VERSION 5.7 ;
BUSBITCHARS "[]" ;
DIVIDERCHAR "/" ;

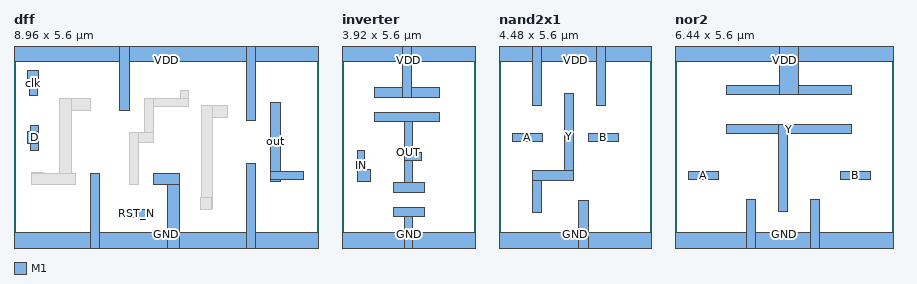
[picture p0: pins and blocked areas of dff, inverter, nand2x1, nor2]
MACRO dff
  CLASS CORE ;
  ORIGIN 0.28 0 ;
  FOREIGN dff -0.28 0 ;
  SIZE 8.96 BY 5.6 ;
  SYMMETRY X Y ;
  SITE core ;
  PIN D
    DIRECTION INOUT ;
    USE SIGNAL ;
    PORT
      LAYER M1 ;
        RECT 0.22 2.705 0.45 3.445 ;
        RECT 0.11 2.91 0.45 3.25 ;
    END
  END D
  PIN clk
    DIRECTION INPUT ;
    USE CLOCK ;
    PORT
      LAYER M1 ;
        RECT 0.115 4.705 0.455 5.045 ;
        RECT 0.17 4.32 0.4 5.045 ;
    END
  END clk
  PIN out
    DIRECTION INOUT ;
    USE SIGNAL ;
    PORT
      LAYER M1 ;
        RECT 7.28 1.845 8.24 2.075 ;
        RECT 7.28 1.795 7.56 4.105 ;
    END
  END out
  PIN RST_N
    DIRECTION INPUT ;
    USE SIGNAL ;
    PORT
      LAYER M1 ;
        RECT 2.87 0.725 3.78 0.955 ;
    END
  END RST_N
  PIN VDD
    DIRECTION INOUT ;
    USE POWER ;
    SHAPE ABUTMENT ;
    PORT
      LAYER M1 ;
        RECT -0.28 5.32 8.68 5.88 ;
        RECT 6.56 3.585 6.84 5.88 ;
        RECT 2.835 3.89 3.115 5.88 ;
    END
  END VDD
  PIN GND
    DIRECTION INOUT ;
    USE GROUND ;
    SHAPE ABUTMENT ;
    PORT
      LAYER M1 ;
        RECT -0.28 -0.28 8.68 0.28 ;
        RECT 6.56 -0.28 6.84 2.315 ;
        RECT 3.83 1.685 4.595 2.025 ;
        RECT 4.255 -0.28 4.595 2.025 ;
        RECT 1.96 -0.28 2.24 2.025 ;
    END
  END GND
  OBS
    LAYER M1 ;
      RECT 5.24 3.675 6.01 4.015 ;
      RECT 5.24 0.98 5.58 4.015 ;
      RECT 5.21 0.96 5.55 1.3 ;
      RECT 4.625 4 4.855 4.475 ;
      RECT 3.555 4 4.855 4.23 ;
      RECT 3.555 2.94 3.835 4.23 ;
      RECT 3.11 2.94 3.835 3.22 ;
      RECT 3.11 1.685 3.39 3.22 ;
      RECT 1.075 3.89 1.965 4.23 ;
      RECT 1.075 1.685 1.415 4.23 ;
      RECT 0.245 1.685 0.585 2.04 ;
      RECT 0.245 1.685 1.52 2.025 ;
  END
END dff

MACRO inverter
  CLASS CORE ;
  ORIGIN 0.28 0 ;
  FOREIGN inverter -0.28 0 ;
  SIZE 3.92 BY 5.6 ;
  SYMMETRY X Y ;
  SITE core ;
  PIN GND
    DIRECTION INOUT ;
    USE GROUND ;
    SHAPE ABUTMENT ;
    PORT
      LAYER M1 ;
        RECT -0.28 -0.28 3.64 0.28 ;
        RECT 1.23 0.74 2.15 1.02 ;
        RECT 1.56 -0.28 1.79 1.02 ;
    END
  END GND
  PIN OUT
    DIRECTION OUTPUT ;
    USE SIGNAL ;
    PORT
      LAYER M1 ;
        RECT 0.67 3.545 2.59 3.825 ;
        RECT 1.23 1.46 2.15 1.74 ;
        RECT 1.575 2.405 2.075 2.635 ;
        RECT 1.575 1.46 1.805 3.825 ;
    END
  END OUT
  PIN IN
    DIRECTION INPUT ;
    USE SIGNAL ;
    PORT
      LAYER M1 ;
        RECT 0.165 1.79 0.565 2.13 ;
        RECT 0.165 1.79 0.395 2.705 ;
    END
  END IN
  PIN VDD
    DIRECTION INOUT ;
    USE POWER ;
    SHAPE ABUTMENT ;
    PORT
      LAYER M1 ;
        RECT -0.28 5.32 3.64 5.88 ;
        RECT 0.67 4.265 2.59 4.545 ;
        RECT 1.49 4.265 1.77 5.88 ;
    END
  END VDD
END inverter

MACRO nand2x1
  CLASS CORE ;
  ORIGIN 0.28 0 ;
  FOREIGN nand2x1 -0.28 0 ;
  SIZE 4.48 BY 5.6 ;
  SYMMETRY X Y ;
  SITE core ;
  PIN VDD
    DIRECTION INOUT ;
    USE POWER ;
    SHAPE ABUTMENT ;
    PORT
      LAYER M1 ;
        RECT -0.28 5.32 4.2 5.88 ;
        RECT 2.58 4.03 2.86 5.88 ;
        RECT 0.7 4.03 0.98 5.88 ;
    END
  END VDD
  PIN A
    DIRECTION INPUT ;
    USE SIGNAL ;
    PORT
      LAYER M1 ;
        RECT 0.11 2.965 0.99 3.195 ;
    END
  END A
  PIN Y
    DIRECTION OUTPUT ;
    USE SIGNAL ;
    PORT
      LAYER M1 ;
        RECT 1.64 1.82 1.92 4.37 ;
        RECT 0.7 1.82 1.92 2.1 ;
        RECT 0.7 0.87 0.98 2.1 ;
    END
  END Y
  PIN B
    DIRECTION INPUT ;
    USE SIGNAL ;
    PORT
      LAYER M1 ;
        RECT 2.365 2.965 3.25 3.195 ;
    END
  END B
  PIN GND
    DIRECTION INOUT ;
    USE GROUND ;
    SHAPE ABUTMENT ;
    PORT
      LAYER M1 ;
        RECT -0.28 -0.28 4.2 0.28 ;
        RECT 2.07 -0.28 2.35 1.21 ;
    END
  END GND
END nand2x1

MACRO nor2
  CLASS CORE ;
  ORIGIN 0.28 0 ;
  FOREIGN nor2 -0.28 0 ;
  SIZE 6.44 BY 5.6 ;
  SYMMETRY X Y ;
  SITE core ;
  PIN GND
    DIRECTION INOUT ;
    USE GROUND ;
    SHAPE ABUTMENT ;
    PORT
      LAYER M1 ;
        RECT -0.28 -0.28 6.16 0.28 ;
        RECT 3.7 -0.28 3.98 1.25 ;
        RECT 1.82 -0.28 2.1 1.25 ;
    END
  END GND
  PIN Y
    DIRECTION OUTPUT ;
    USE SIGNAL ;
    PORT
      LAYER M1 ;
        RECT 1.23 3.19 4.91 3.47 ;
        RECT 2.76 0.91 3.04 3.47 ;
    END
  END Y
  PIN A
    DIRECTION INPUT ;
    USE SIGNAL ;
    PORT
      LAYER M1 ;
        RECT 0.125 1.845 1.01 2.075 ;
    END
  END A
  PIN B
    DIRECTION INPUT ;
    USE SIGNAL ;
    PORT
      LAYER M1 ;
        RECT 4.59 1.845 5.475 2.075 ;
    END
  END B
  PIN VDD
    DIRECTION INOUT ;
    USE POWER ;
    SHAPE ABUTMENT ;
    PORT
      LAYER M1 ;
        RECT -0.28 5.32 6.16 5.88 ;
        RECT 1.23 4.34 4.91 4.62 ;
        RECT 2.795 4.34 3.355 5.88 ;
    END
  END VDD
END nor2

END LIBRARY
